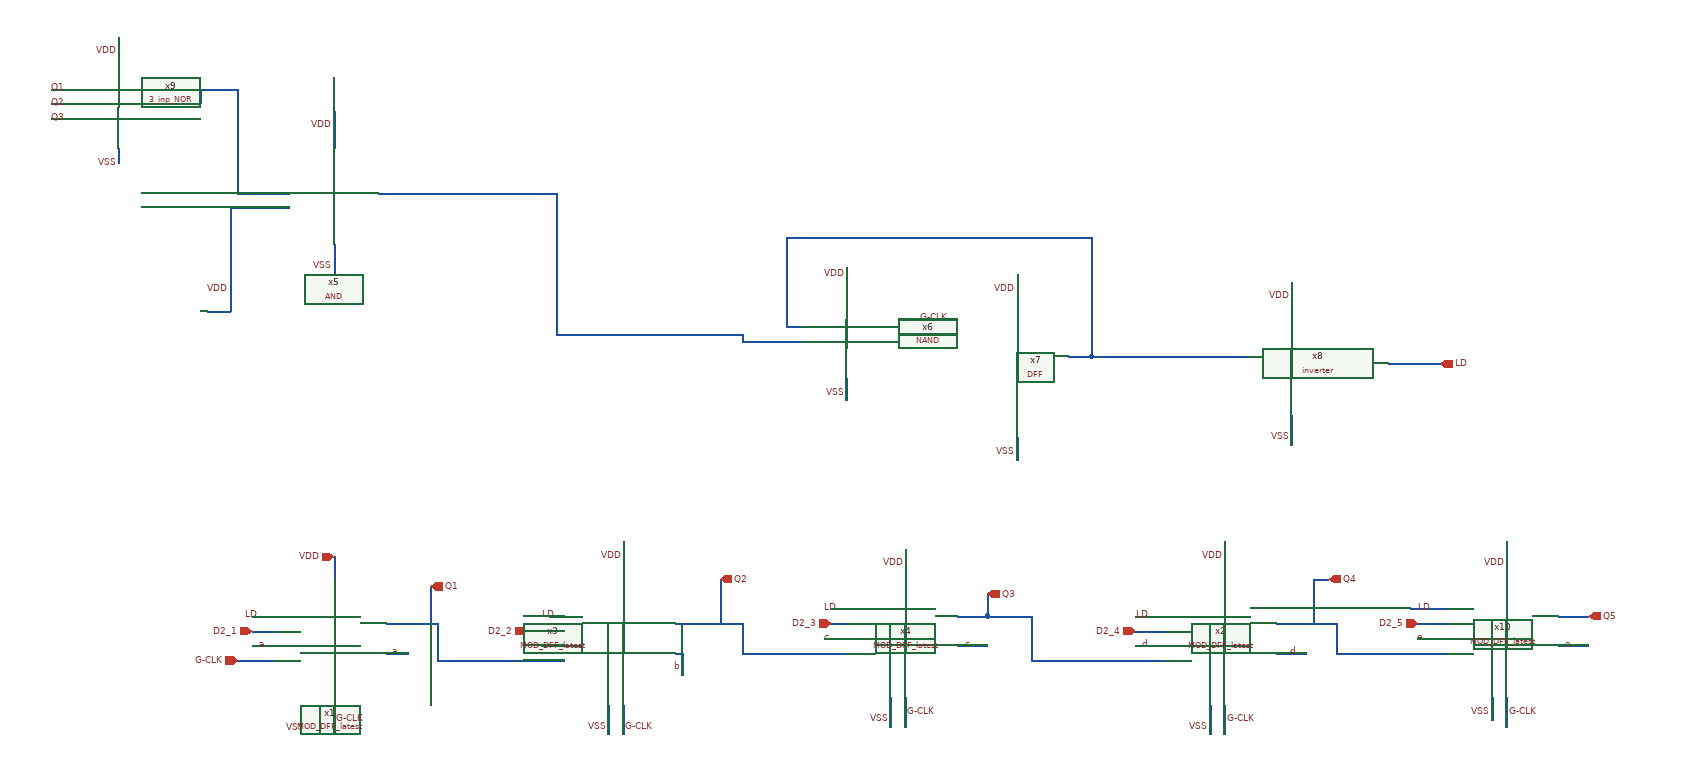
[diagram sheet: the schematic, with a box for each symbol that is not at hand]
v {xschem version=3.1.0 file_version=1.2
}
G {}
K {}
V {}
S {}
E {}
N -490 10 -460 10 {
lab=a}
N -670 -20 -640 -20 {
lab=D2_1}
N -670 0 -640 0 {
lab=a}
N -560 -120 -560 -90 {
lab=VDD}
N -580 80 -580 110 {
lab=VSS}
N 860 -380 900 -380 {
lab=LD}
N -670 -40 -640 -40 {
lab=LD}
N -270 -40 -250 -40 {
lab=LD}
N -940 -750 -900 -750 {
lab=Q1}
N -10 -410 70 -410 {
lab=#net1}
N 460 -550 460 -390 {
lab=#net2}
N 50 -550 50 -430 {
lab=#net2}
N 50 -430 70 -430 {
lab=#net2}
N 460 -390 520 -390 {
lab=#net2}
N 360 -500 360 -470 {
lab=VDD}
N 130 -510 130 -480 {
lab=VDD}
N 130 -360 130 -330 {
lab=VSS}
N 360 -280 360 -250 {
lab=VSS}
N -170 -140 -170 -90 {
lab=VDD}
N 280 0 320 0 {
lab=c}
N -100 10 -90 10 {
lab=b}
N -90 10 -90 40 {
lab=b}
N 110 -30 130 -30 {
lab=D2_3}
N -270 -20 -250 -20 {
lab=D2_2}
N -40 -90 -40 -40 {
lab=Q2}
N 280 -40 320 -40 {
lab=Q3}
N -300 -20 -270 -20 {
lab=D2_2}
N 210 -130 210 -100 {
lab=VDD}
N 190 70 190 110 {
lab=VSS}
N -280 0 -250 0 {
lab=b}
N 100 -10 130 -10 {
lab=c}
N 250 -440 280 -440 {
lab=G-CLK}
N 110 -50 130 -50 {
lab=LD}
N -40 -40 -40 -30 {
lab=Q2}
N -210 -420 -20 -420 {
lab=#net1}
N -10 -420 -10 -410 {
lab=#net1}
N -20 -420 -10 -420 {
lab=#net1}
N 520 -390 670 -390 {
lab=#net2}
N 900 -380 930 -380 {
lab=LD}
N 200 -420 280 -420 {
lab=#net3}
N -190 80 -190 120 {
lab=VSS}
N 320 -70 320 -40 {
lab=Q3}
N 520 -20 560 -20 {
lab=D2_4}
N 520 0 560 0 {
lab=d}
N 640 -140 640 -90 {
lab=VDD}
N 620 80 620 120 {
lab=VSS}
N -850 -820 -850 -790 {
lab=VDD}
N -850 -670 -850 -650 {
lab=VSS}
N -940 -730 -900 -730 {
lab=Q2}
N -730 -750 -690 -750 {
lab=#net4}
N -690 -750 -690 -610 {
lab=#net4}
N -690 -610 -620 -610 {
lab=#net4}
N -730 -450 -700 -450 {
lab=VDD}
N -700 -590 -700 -450 {
lab=VDD}
N -700 -590 -620 -590 {
lab=VDD}
N -260 -590 -260 -420 {
lab=#net1}
N -260 -420 -210 -420 {
lab=#net1}
N 890 -50 940 -50 {
lab=LD}
N 900 -30 940 -30 {
lab=D2_5}
N 760 -90 760 -30 {
lab=Q4}
N 760 -90 780 -90 {
lab=Q4}
N 900 -10 940 -10 {
lab=e}
N 1090 -40 1130 -40 {
lab=Q5}
N 1090 0 1130 0 {
lab=e}
N 1020 -140 1020 -100 {
lab=VDD}
N 1000 70 1000 100 {
lab=VSS}
N -740 -750 -740 -730 {
lab=#net4}
N -740 -750 -730 -750 {
lab=#net4}
N -940 -710 -900 -710 {
lab=Q3}
N 430 -390 460 -390 {
lab=#net2}
N 50 -550 460 -550 {
lab=#net2}
N 730 -490 730 -450 {
lab=VDD}
N 730 -310 730 -270 {
lab=VSS}
N -560 80 -560 120 {
lab=G-CLK}
N -690 20 -640 20 {
lab=G-CLK}
N -170 80 -170 120 {
lab=G-CLK}
N -490 -30 -420 -30 {
lab=Q1}
N -420 -30 -420 20 {
lab=Q1}
N -420 20 -250 20 {
lab=Q1}
N -430 -80 -430 -30 {
lab=Q1}
N -100 -30 -10 -30 {
lab=Q2}
N -10 -30 -10 10 {
lab=Q2}
N -10 10 130 10 {
lab=Q2}
N 520 -40 560 -40 {
lab=LD}
N 210 70 210 110 {
lab=G-CLK}
N 710 10 750 10 {
lab=d}
N 320 -40 380 -40 {
lab=Q3}
N 380 -40 380 20 {
lab=Q3}
N 380 20 560 20 {
lab=Q3}
N 640 80 640 120 {
lab=G-CLK}
N 710 -30 790 -30 {
lab=Q4}
N 790 -30 790 10 {
lab=Q4}
N 790 10 940 10 {
lab=Q4}
N 1020 70 1020 110 {
lab=G-CLK}
N -500 -610 -260 -610 {
lab=#net1}
N -260 -610 -260 -590 {
lab=#net1}
N -560 -720 -560 -670 {
lab=VDD}
N -560 -540 -560 -500 {
lab=VSS}
C {devices/lab_wire.sym} -660 -40 0 0 {name=p2 sig_type=std_logic lab=LD}
C {devices/lab_wire.sym} -260 -40 0 0 {name=p3 sig_type=std_logic lab=LD}
C {devices/iopin.sym} -560 -120 3 0 {name=p4 lab=VDD}
C {devices/iopin.sym} -580 110 1 0 {name=p5 lab=VSS}
C {devices/lab_wire.sym} 130 -500 0 0 {name=p8 sig_type=std_logic lab=VDD}
C {devices/lab_wire.sym} 360 -480 0 0 {name=p9 sig_type=std_logic lab=VDD}
C {devices/lab_wire.sym} -170 -120 0 0 {name=p11 sig_type=std_logic lab=VDD}
C {devices/lab_wire.sym} 130 -340 0 0 {name=p12 sig_type=std_logic lab=VSS}
C {devices/lab_wire.sym} 360 -260 0 0 {name=p13 sig_type=std_logic lab=VSS}
C {devices/lab_wire.sym} -190 110 0 0 {name=p15 sig_type=std_logic lab=VSS}
C {devices/opin.sym} 320 -70 3 0 {name=p16 lab=Q3}
C {devices/opin.sym} -430 -80 3 0 {name=p17 lab=Q1}
C {devices/ipin.sym} -670 -20 0 0 {name=p18 lab=D2_1}
C {devices/ipin.sym} -300 -20 0 0 {name=p19 lab=D2_2}
C {devices/lab_wire.sym} 210 -110 0 0 {name=p22 sig_type=std_logic lab=VDD}
C {devices/lab_wire.sym} 190 100 0 0 {name=p23 sig_type=std_logic lab=VSS}
C {devices/ipin.sym} 110 -30 0 0 {name=p24 lab=D2_3}
C {devices/lab_wire.sym} -470 10 0 0 {name=p32 sig_type=std_logic lab=a}
C {devices/lab_wire.sym} -270 0 0 0 {name=p33 sig_type=std_logic lab=b}
C {devices/lab_wire.sym} -90 30 0 0 {name=p34 sig_type=std_logic lab=b}
C {devices/lab_wire.sym} 300 0 0 0 {name=p35 sig_type=std_logic lab=c}
C {devices/lab_wire.sym} 110 -10 0 0 {name=p36 sig_type=std_logic lab=c}
C {devices/ipin.sym} -690 20 0 0 {name=p37 lab=G-CLK}
C {devices/lab_wire.sym} 270 -440 0 0 {name=p38 sig_type=std_logic lab=G-CLK}
C {devices/opin.sym} -40 -90 3 0 {name=p39 lab=Q2}
C {devices/lab_wire.sym} 120 -50 0 0 {name=p40 sig_type=std_logic lab=LD}
C {devices/opin.sym} 930 -380 0 0 {name=p41 lab=LD}
C {NAND.sym} 220 -410 0 0 {name=x6}
C {devices/lab_wire.sym} 540 0 0 0 {name=p20 sig_type=std_logic lab=d}
C {devices/ipin.sym} 520 -20 0 0 {name=p21 lab=D2_4}
C {devices/lab_wire.sym} 640 -120 0 0 {name=p25 sig_type=std_logic lab=VDD}
C {devices/lab_wire.sym} 620 110 0 0 {name=p26 sig_type=std_logic lab=VSS}
C {devices/opin.sym} 780 -90 0 0 {name=p43 lab=Q4}
C {devices/lab_wire.sym} -850 -650 0 0 {name=p44 sig_type=std_logic lab=VSS}
C {devices/lab_wire.sym} -850 -800 0 0 {name=p45 sig_type=std_logic lab=VDD}
C {devices/ipin.sym} 900 -30 0 0 {name=p51 lab=D2_5}
C {devices/opin.sym} 1130 -40 0 0 {name=p52 lab=Q5}
C {devices/lab_wire.sym} 910 -10 0 0 {name=p53 sig_type=std_logic lab=e}
C {devices/lab_wire.sym} 1110 0 0 0 {name=p54 sig_type=std_logic lab=e}
C {devices/lab_wire.sym} 920 -50 0 0 {name=p55 sig_type=std_logic lab=LD}
C {devices/lab_wire.sym} 1020 -110 0 0 {name=p56 sig_type=std_logic lab=VDD}
C {devices/lab_wire.sym} 1000 90 0 0 {name=p57 sig_type=std_logic lab=VSS}
C {3_inp_NOR.sym} -530 -630 0 0 {name=x9}
C {DFF.sym} 430 -420 0 0 {name=x7}
C {devices/lab_wire.sym} 730 -470 0 0 {name=p59 sig_type=std_logic lab=VDD}
C {devices/lab_wire.sym} 730 -280 0 0 {name=p60 sig_type=std_logic lab=VSS}
C {inverter.sym} 820 -370 0 0 {name=x8}
C {MOD_DFF_latest.sym} -490 0 0 0 {name=x1}
C {devices/lab_wire.sym} -650 0 0 0 {name=p10 sig_type=std_logic lab=a}
C {devices/lab_wire.sym} -560 100 2 0 {name=p14 sig_type=std_logic lab=G-CLK}
C {MOD_DFF_latest.sym} -100 0 0 0 {name=x3}
C {devices/lab_wire.sym} -170 110 2 0 {name=p31 sig_type=std_logic lab=G-CLK}
C {MOD_DFF_latest.sym} 280 -10 0 0 {name=x4}
C {MOD_DFF_latest.sym} 710 0 0 0 {name=x2}
C {devices/lab_wire.sym} 540 -40 0 0 {name=p61 sig_type=std_logic lab=LD}
C {devices/lab_wire.sym} 210 90 2 0 {name=p62 sig_type=std_logic lab=G-CLK}
C {devices/lab_wire.sym} 740 10 0 0 {name=p1 sig_type=std_logic lab=d}
C {MOD_DFF_latest.sym} 1090 -10 0 0 {name=x10}
C {devices/lab_wire.sym} 640 100 2 0 {name=p42 sig_type=std_logic lab=G-CLK}
C {devices/lab_wire.sym} 1020 90 2 0 {name=p63 sig_type=std_logic lab=G-CLK}
C {devices/lab_wire.sym} -920 -750 0 0 {name=p27 sig_type=std_logic lab=Q1}
C {devices/lab_wire.sym} -920 -730 0 0 {name=p28 sig_type=std_logic lab=Q2}
C {devices/lab_wire.sym} -920 -710 0 0 {name=p29 sig_type=std_logic lab=Q3}
C {AND.sym} -470 -590 0 0 {name=x5}
C {devices/lab_wire.sym} -560 -700 0 0 {name=p47 sig_type=std_logic lab=VDD}
C {devices/lab_wire.sym} -560 -510 0 0 {name=p48 sig_type=std_logic lab=VSS}
C {devices/lab_wire.sym} -700 -480 0 0 {name=p6 sig_type=std_logic lab=VDD}
